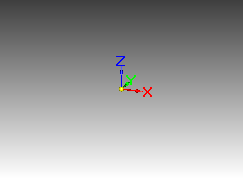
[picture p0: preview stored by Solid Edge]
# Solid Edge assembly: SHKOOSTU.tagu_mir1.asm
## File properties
Author: Türk
Template: Iso Assembly.asm
Last saved by: Türk
Revision: 2
Application: Solid Edge
Username: Türk
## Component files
ShKolvikoostu_mir.asm
Shockabsorber.par
Poldikoostu5_mir.asm
Taguminevedru_mir1.par
Shkaan.par
